# OpenTallas memory compiler (tools/mem_compiler), ASAP7 abstract view
VERSION 5.7 ;
BUSBITCHARS "[]" ;
DIVIDERCHAR "/" ;
PROPERTYDEFINITIONS
  MACRO width INTEGER ;
  MACRO depth INTEGER ;
  MACRO banks INTEGER ;
END PROPERTYDEFINITIONS
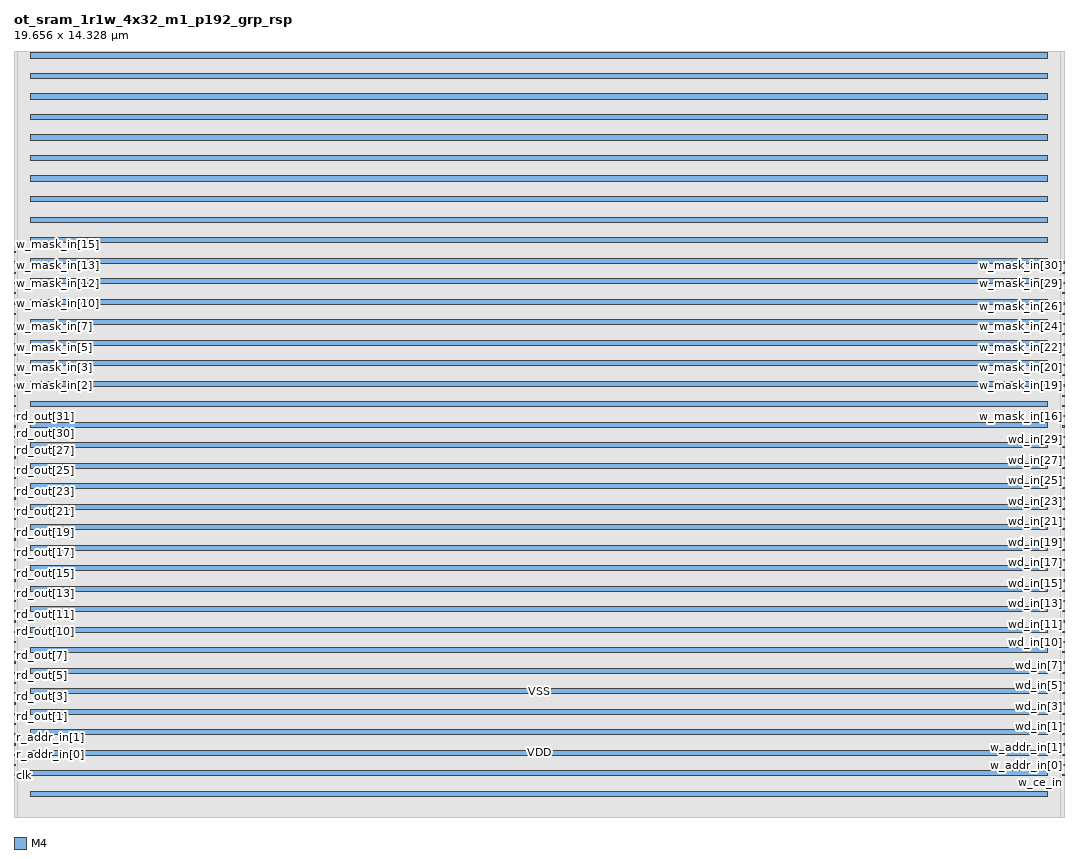
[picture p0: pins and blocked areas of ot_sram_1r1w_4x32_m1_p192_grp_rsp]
MACRO ot_sram_1r1w_4x32_m1_p192_grp_rsp
  PROPERTY width 32 ;
  PROPERTY depth 4 ;
  PROPERTY banks 1 ;
  FOREIGN ot_sram_1r1w_4x32_m1_p192_grp_rsp 0 0 ;
  SYMMETRY X Y R90 ;
  SIZE 19.656 BY 14.328 ;
  CLASS BLOCK ;
  PIN clk
    DIRECTION INPUT ;
    USE CLOCK ;
    SHAPE ABUTMENT ;
    PORT
      LAYER M4 ;
      RECT 0.000 0.768 0.024 0.792 ;
    END
  END clk
  PIN r_ce_in
    DIRECTION INPUT ;
    USE SIGNAL ;
    SHAPE ABUTMENT ;
    PORT
      LAYER M4 ;
      RECT 0.000 0.960 0.024 0.984 ;
    END
  END r_ce_in
  PIN r_addr_in[0]
    DIRECTION INPUT ;
    USE SIGNAL ;
    SHAPE ABUTMENT ;
    PORT
      LAYER M4 ;
      RECT 0.000 1.152 0.024 1.176 ;
    END
  END r_addr_in[0]
  PIN r_addr_in[1]
    DIRECTION INPUT ;
    USE SIGNAL ;
    SHAPE ABUTMENT ;
    PORT
      LAYER M4 ;
      RECT 0.000 1.344 0.024 1.368 ;
    END
  END r_addr_in[1]
  PIN rd_out[0]
    DIRECTION OUTPUT ;
    USE SIGNAL ;
    SHAPE ABUTMENT ;
    PORT
      LAYER M4 ;
      RECT 0.000 1.536 0.024 1.560 ;
    END
  END rd_out[0]
  PIN rd_out[1]
    DIRECTION OUTPUT ;
    USE SIGNAL ;
    SHAPE ABUTMENT ;
    PORT
      LAYER M4 ;
      RECT 0.000 1.728 0.024 1.752 ;
    END
  END rd_out[1]
  PIN rd_out[2]
    DIRECTION OUTPUT ;
    USE SIGNAL ;
    SHAPE ABUTMENT ;
    PORT
      LAYER M4 ;
      RECT 0.000 1.920 0.024 1.944 ;
    END
  END rd_out[2]
  PIN rd_out[3]
    DIRECTION OUTPUT ;
    USE SIGNAL ;
    SHAPE ABUTMENT ;
    PORT
      LAYER M4 ;
      RECT 0.000 2.112 0.024 2.136 ;
    END
  END rd_out[3]
  PIN rd_out[4]
    DIRECTION OUTPUT ;
    USE SIGNAL ;
    SHAPE ABUTMENT ;
    PORT
      LAYER M4 ;
      RECT 0.000 2.304 0.024 2.328 ;
    END
  END rd_out[4]
  PIN rd_out[5]
    DIRECTION OUTPUT ;
    USE SIGNAL ;
    SHAPE ABUTMENT ;
    PORT
      LAYER M4 ;
      RECT 0.000 2.496 0.024 2.520 ;
    END
  END rd_out[5]
  PIN rd_out[6]
    DIRECTION OUTPUT ;
    USE SIGNAL ;
    SHAPE ABUTMENT ;
    PORT
      LAYER M4 ;
      RECT 0.000 2.688 0.024 2.712 ;
    END
  END rd_out[6]
  PIN rd_out[7]
    DIRECTION OUTPUT ;
    USE SIGNAL ;
    SHAPE ABUTMENT ;
    PORT
      LAYER M4 ;
      RECT 0.000 2.880 0.024 2.904 ;
    END
  END rd_out[7]
  PIN rd_out[8]
    DIRECTION OUTPUT ;
    USE SIGNAL ;
    SHAPE ABUTMENT ;
    PORT
      LAYER M4 ;
      RECT 0.000 3.072 0.024 3.096 ;
    END
  END rd_out[8]
  PIN rd_out[9]
    DIRECTION OUTPUT ;
    USE SIGNAL ;
    SHAPE ABUTMENT ;
    PORT
      LAYER M4 ;
      RECT 0.000 3.264 0.024 3.288 ;
    END
  END rd_out[9]
  PIN rd_out[10]
    DIRECTION OUTPUT ;
    USE SIGNAL ;
    SHAPE ABUTMENT ;
    PORT
      LAYER M4 ;
      RECT 0.000 3.456 0.024 3.480 ;
    END
  END rd_out[10]
  PIN rd_out[11]
    DIRECTION OUTPUT ;
    USE SIGNAL ;
    SHAPE ABUTMENT ;
    PORT
      LAYER M4 ;
      RECT 0.000 3.648 0.024 3.672 ;
    END
  END rd_out[11]
  PIN rd_out[12]
    DIRECTION OUTPUT ;
    USE SIGNAL ;
    SHAPE ABUTMENT ;
    PORT
      LAYER M4 ;
      RECT 0.000 3.840 0.024 3.864 ;
    END
  END rd_out[12]
  PIN rd_out[13]
    DIRECTION OUTPUT ;
    USE SIGNAL ;
    SHAPE ABUTMENT ;
    PORT
      LAYER M4 ;
      RECT 0.000 4.032 0.024 4.056 ;
    END
  END rd_out[13]
  PIN rd_out[14]
    DIRECTION OUTPUT ;
    USE SIGNAL ;
    SHAPE ABUTMENT ;
    PORT
      LAYER M4 ;
      RECT 0.000 4.224 0.024 4.248 ;
    END
  END rd_out[14]
  PIN rd_out[15]
    DIRECTION OUTPUT ;
    USE SIGNAL ;
    SHAPE ABUTMENT ;
    PORT
      LAYER M4 ;
      RECT 0.000 4.416 0.024 4.440 ;
    END
  END rd_out[15]
  PIN rd_out[16]
    DIRECTION OUTPUT ;
    USE SIGNAL ;
    SHAPE ABUTMENT ;
    PORT
      LAYER M4 ;
      RECT 0.000 4.608 0.024 4.632 ;
    END
  END rd_out[16]
  PIN rd_out[17]
    DIRECTION OUTPUT ;
    USE SIGNAL ;
    SHAPE ABUTMENT ;
    PORT
      LAYER M4 ;
      RECT 0.000 4.800 0.024 4.824 ;
    END
  END rd_out[17]
  PIN rd_out[18]
    DIRECTION OUTPUT ;
    USE SIGNAL ;
    SHAPE ABUTMENT ;
    PORT
      LAYER M4 ;
      RECT 0.000 4.992 0.024 5.016 ;
    END
  END rd_out[18]
  PIN rd_out[19]
    DIRECTION OUTPUT ;
    USE SIGNAL ;
    SHAPE ABUTMENT ;
    PORT
      LAYER M4 ;
      RECT 0.000 5.184 0.024 5.208 ;
    END
  END rd_out[19]
  PIN rd_out[20]
    DIRECTION OUTPUT ;
    USE SIGNAL ;
    SHAPE ABUTMENT ;
    PORT
      LAYER M4 ;
      RECT 0.000 5.376 0.024 5.400 ;
    END
  END rd_out[20]
  PIN rd_out[21]
    DIRECTION OUTPUT ;
    USE SIGNAL ;
    SHAPE ABUTMENT ;
    PORT
      LAYER M4 ;
      RECT 0.000 5.568 0.024 5.592 ;
    END
  END rd_out[21]
  PIN rd_out[22]
    DIRECTION OUTPUT ;
    USE SIGNAL ;
    SHAPE ABUTMENT ;
    PORT
      LAYER M4 ;
      RECT 0.000 5.760 0.024 5.784 ;
    END
  END rd_out[22]
  PIN rd_out[23]
    DIRECTION OUTPUT ;
    USE SIGNAL ;
    SHAPE ABUTMENT ;
    PORT
      LAYER M4 ;
      RECT 0.000 5.952 0.024 5.976 ;
    END
  END rd_out[23]
  PIN rd_out[24]
    DIRECTION OUTPUT ;
    USE SIGNAL ;
    SHAPE ABUTMENT ;
    PORT
      LAYER M4 ;
      RECT 0.000 6.144 0.024 6.168 ;
    END
  END rd_out[24]
  PIN rd_out[25]
    DIRECTION OUTPUT ;
    USE SIGNAL ;
    SHAPE ABUTMENT ;
    PORT
      LAYER M4 ;
      RECT 0.000 6.336 0.024 6.360 ;
    END
  END rd_out[25]
  PIN rd_out[26]
    DIRECTION OUTPUT ;
    USE SIGNAL ;
    SHAPE ABUTMENT ;
    PORT
      LAYER M4 ;
      RECT 0.000 6.528 0.024 6.552 ;
    END
  END rd_out[26]
  PIN rd_out[27]
    DIRECTION OUTPUT ;
    USE SIGNAL ;
    SHAPE ABUTMENT ;
    PORT
      LAYER M4 ;
      RECT 0.000 6.720 0.024 6.744 ;
    END
  END rd_out[27]
  PIN rd_out[28]
    DIRECTION OUTPUT ;
    USE SIGNAL ;
    SHAPE ABUTMENT ;
    PORT
      LAYER M4 ;
      RECT 0.000 6.912 0.024 6.936 ;
    END
  END rd_out[28]
  PIN rd_out[29]
    DIRECTION OUTPUT ;
    USE SIGNAL ;
    SHAPE ABUTMENT ;
    PORT
      LAYER M4 ;
      RECT 0.000 7.104 0.024 7.128 ;
    END
  END rd_out[29]
  PIN rd_out[30]
    DIRECTION OUTPUT ;
    USE SIGNAL ;
    SHAPE ABUTMENT ;
    PORT
      LAYER M4 ;
      RECT 0.000 7.296 0.024 7.320 ;
    END
  END rd_out[30]
  PIN rd_out[31]
    DIRECTION OUTPUT ;
    USE SIGNAL ;
    SHAPE ABUTMENT ;
    PORT
      LAYER M4 ;
      RECT 0.000 7.488 0.024 7.512 ;
    END
  END rd_out[31]
  PIN w_mask_in[0]
    DIRECTION INPUT ;
    USE SIGNAL ;
    SHAPE ABUTMENT ;
    PORT
      LAYER M4 ;
      RECT 0.000 7.680 0.024 7.704 ;
    END
  END w_mask_in[0]
  PIN w_mask_in[1]
    DIRECTION INPUT ;
    USE SIGNAL ;
    SHAPE ABUTMENT ;
    PORT
      LAYER M4 ;
      RECT 0.000 7.872 0.024 7.896 ;
    END
  END w_mask_in[1]
  PIN w_mask_in[2]
    DIRECTION INPUT ;
    USE SIGNAL ;
    SHAPE ABUTMENT ;
    PORT
      LAYER M4 ;
      RECT 0.000 8.064 0.024 8.088 ;
    END
  END w_mask_in[2]
  PIN w_mask_in[3]
    DIRECTION INPUT ;
    USE SIGNAL ;
    SHAPE ABUTMENT ;
    PORT
      LAYER M4 ;
      RECT 0.000 8.256 0.024 8.280 ;
    END
  END w_mask_in[3]
  PIN w_mask_in[4]
    DIRECTION INPUT ;
    USE SIGNAL ;
    SHAPE ABUTMENT ;
    PORT
      LAYER M4 ;
      RECT 0.000 8.448 0.024 8.472 ;
    END
  END w_mask_in[4]
  PIN w_mask_in[5]
    DIRECTION INPUT ;
    USE SIGNAL ;
    SHAPE ABUTMENT ;
    PORT
      LAYER M4 ;
      RECT 0.000 8.640 0.024 8.664 ;
    END
  END w_mask_in[5]
  PIN w_mask_in[6]
    DIRECTION INPUT ;
    USE SIGNAL ;
    SHAPE ABUTMENT ;
    PORT
      LAYER M4 ;
      RECT 0.000 8.832 0.024 8.856 ;
    END
  END w_mask_in[6]
  PIN w_mask_in[7]
    DIRECTION INPUT ;
    USE SIGNAL ;
    SHAPE ABUTMENT ;
    PORT
      LAYER M4 ;
      RECT 0.000 9.024 0.024 9.048 ;
    END
  END w_mask_in[7]
  PIN w_mask_in[8]
    DIRECTION INPUT ;
    USE SIGNAL ;
    SHAPE ABUTMENT ;
    PORT
      LAYER M4 ;
      RECT 0.000 9.216 0.024 9.240 ;
    END
  END w_mask_in[8]
  PIN w_mask_in[9]
    DIRECTION INPUT ;
    USE SIGNAL ;
    SHAPE ABUTMENT ;
    PORT
      LAYER M4 ;
      RECT 0.000 9.408 0.024 9.432 ;
    END
  END w_mask_in[9]
  PIN w_mask_in[10]
    DIRECTION INPUT ;
    USE SIGNAL ;
    SHAPE ABUTMENT ;
    PORT
      LAYER M4 ;
      RECT 0.000 9.600 0.024 9.624 ;
    END
  END w_mask_in[10]
  PIN w_mask_in[11]
    DIRECTION INPUT ;
    USE SIGNAL ;
    SHAPE ABUTMENT ;
    PORT
      LAYER M4 ;
      RECT 0.000 9.792 0.024 9.816 ;
    END
  END w_mask_in[11]
  PIN w_mask_in[12]
    DIRECTION INPUT ;
    USE SIGNAL ;
    SHAPE ABUTMENT ;
    PORT
      LAYER M4 ;
      RECT 0.000 9.984 0.024 10.008 ;
    END
  END w_mask_in[12]
  PIN w_mask_in[13]
    DIRECTION INPUT ;
    USE SIGNAL ;
    SHAPE ABUTMENT ;
    PORT
      LAYER M4 ;
      RECT 0.000 10.176 0.024 10.200 ;
    END
  END w_mask_in[13]
  PIN w_mask_in[14]
    DIRECTION INPUT ;
    USE SIGNAL ;
    SHAPE ABUTMENT ;
    PORT
      LAYER M4 ;
      RECT 0.000 10.368 0.024 10.392 ;
    END
  END w_mask_in[14]
  PIN w_mask_in[15]
    DIRECTION INPUT ;
    USE SIGNAL ;
    SHAPE ABUTMENT ;
    PORT
      LAYER M4 ;
      RECT 0.000 10.560 0.024 10.584 ;
    END
  END w_mask_in[15]
  PIN w_ce_in
    DIRECTION INPUT ;
    USE SIGNAL ;
    SHAPE ABUTMENT ;
    PORT
      LAYER M4 ;
      RECT 19.632 0.768 19.656 0.792 ;
    END
  END w_ce_in
  PIN w_addr_in[0]
    DIRECTION INPUT ;
    USE SIGNAL ;
    SHAPE ABUTMENT ;
    PORT
      LAYER M4 ;
      RECT 19.632 0.960 19.656 0.984 ;
    END
  END w_addr_in[0]
  PIN w_addr_in[1]
    DIRECTION INPUT ;
    USE SIGNAL ;
    SHAPE ABUTMENT ;
    PORT
      LAYER M4 ;
      RECT 19.632 1.152 19.656 1.176 ;
    END
  END w_addr_in[1]
  PIN wd_in[0]
    DIRECTION INPUT ;
    USE SIGNAL ;
    SHAPE ABUTMENT ;
    PORT
      LAYER M4 ;
      RECT 19.632 1.344 19.656 1.368 ;
    END
  END wd_in[0]
  PIN wd_in[1]
    DIRECTION INPUT ;
    USE SIGNAL ;
    SHAPE ABUTMENT ;
    PORT
      LAYER M4 ;
      RECT 19.632 1.536 19.656 1.560 ;
    END
  END wd_in[1]
  PIN wd_in[2]
    DIRECTION INPUT ;
    USE SIGNAL ;
    SHAPE ABUTMENT ;
    PORT
      LAYER M4 ;
      RECT 19.632 1.728 19.656 1.752 ;
    END
  END wd_in[2]
  PIN wd_in[3]
    DIRECTION INPUT ;
    USE SIGNAL ;
    SHAPE ABUTMENT ;
    PORT
      LAYER M4 ;
      RECT 19.632 1.920 19.656 1.944 ;
    END
  END wd_in[3]
  PIN wd_in[4]
    DIRECTION INPUT ;
    USE SIGNAL ;
    SHAPE ABUTMENT ;
    PORT
      LAYER M4 ;
      RECT 19.632 2.112 19.656 2.136 ;
    END
  END wd_in[4]
  PIN wd_in[5]
    DIRECTION INPUT ;
    USE SIGNAL ;
    SHAPE ABUTMENT ;
    PORT
      LAYER M4 ;
      RECT 19.632 2.304 19.656 2.328 ;
    END
  END wd_in[5]
  PIN wd_in[6]
    DIRECTION INPUT ;
    USE SIGNAL ;
    SHAPE ABUTMENT ;
    PORT
      LAYER M4 ;
      RECT 19.632 2.496 19.656 2.520 ;
    END
  END wd_in[6]
  PIN wd_in[7]
    DIRECTION INPUT ;
    USE SIGNAL ;
    SHAPE ABUTMENT ;
    PORT
      LAYER M4 ;
      RECT 19.632 2.688 19.656 2.712 ;
    END
  END wd_in[7]
  PIN wd_in[8]
    DIRECTION INPUT ;
    USE SIGNAL ;
    SHAPE ABUTMENT ;
    PORT
      LAYER M4 ;
      RECT 19.632 2.880 19.656 2.904 ;
    END
  END wd_in[8]
  PIN wd_in[9]
    DIRECTION INPUT ;
    USE SIGNAL ;
    SHAPE ABUTMENT ;
    PORT
      LAYER M4 ;
      RECT 19.632 3.072 19.656 3.096 ;
    END
  END wd_in[9]
  PIN wd_in[10]
    DIRECTION INPUT ;
    USE SIGNAL ;
    SHAPE ABUTMENT ;
    PORT
      LAYER M4 ;
      RECT 19.632 3.264 19.656 3.288 ;
    END
  END wd_in[10]
  PIN wd_in[11]
    DIRECTION INPUT ;
    USE SIGNAL ;
    SHAPE ABUTMENT ;
    PORT
      LAYER M4 ;
      RECT 19.632 3.456 19.656 3.480 ;
    END
  END wd_in[11]
  PIN wd_in[12]
    DIRECTION INPUT ;
    USE SIGNAL ;
    SHAPE ABUTMENT ;
    PORT
      LAYER M4 ;
      RECT 19.632 3.648 19.656 3.672 ;
    END
  END wd_in[12]
  PIN wd_in[13]
    DIRECTION INPUT ;
    USE SIGNAL ;
    SHAPE ABUTMENT ;
    PORT
      LAYER M4 ;
      RECT 19.632 3.840 19.656 3.864 ;
    END
  END wd_in[13]
  PIN wd_in[14]
    DIRECTION INPUT ;
    USE SIGNAL ;
    SHAPE ABUTMENT ;
    PORT
      LAYER M4 ;
      RECT 19.632 4.032 19.656 4.056 ;
    END
  END wd_in[14]
  PIN wd_in[15]
    DIRECTION INPUT ;
    USE SIGNAL ;
    SHAPE ABUTMENT ;
    PORT
      LAYER M4 ;
      RECT 19.632 4.224 19.656 4.248 ;
    END
  END wd_in[15]
  PIN wd_in[16]
    DIRECTION INPUT ;
    USE SIGNAL ;
    SHAPE ABUTMENT ;
    PORT
      LAYER M4 ;
      RECT 19.632 4.416 19.656 4.440 ;
    END
  END wd_in[16]
  PIN wd_in[17]
    DIRECTION INPUT ;
    USE SIGNAL ;
    SHAPE ABUTMENT ;
    PORT
      LAYER M4 ;
      RECT 19.632 4.608 19.656 4.632 ;
    END
  END wd_in[17]
  PIN wd_in[18]
    DIRECTION INPUT ;
    USE SIGNAL ;
    SHAPE ABUTMENT ;
    PORT
      LAYER M4 ;
      RECT 19.632 4.800 19.656 4.824 ;
    END
  END wd_in[18]
  PIN wd_in[19]
    DIRECTION INPUT ;
    USE SIGNAL ;
    SHAPE ABUTMENT ;
    PORT
      LAYER M4 ;
      RECT 19.632 4.992 19.656 5.016 ;
    END
  END wd_in[19]
  PIN wd_in[20]
    DIRECTION INPUT ;
    USE SIGNAL ;
    SHAPE ABUTMENT ;
    PORT
      LAYER M4 ;
      RECT 19.632 5.184 19.656 5.208 ;
    END
  END wd_in[20]
  PIN wd_in[21]
    DIRECTION INPUT ;
    USE SIGNAL ;
    SHAPE ABUTMENT ;
    PORT
      LAYER M4 ;
      RECT 19.632 5.376 19.656 5.400 ;
    END
  END wd_in[21]
  PIN wd_in[22]
    DIRECTION INPUT ;
    USE SIGNAL ;
    SHAPE ABUTMENT ;
    PORT
      LAYER M4 ;
      RECT 19.632 5.568 19.656 5.592 ;
    END
  END wd_in[22]
  PIN wd_in[23]
    DIRECTION INPUT ;
    USE SIGNAL ;
    SHAPE ABUTMENT ;
    PORT
      LAYER M4 ;
      RECT 19.632 5.760 19.656 5.784 ;
    END
  END wd_in[23]
  PIN wd_in[24]
    DIRECTION INPUT ;
    USE SIGNAL ;
    SHAPE ABUTMENT ;
    PORT
      LAYER M4 ;
      RECT 19.632 5.952 19.656 5.976 ;
    END
  END wd_in[24]
  PIN wd_in[25]
    DIRECTION INPUT ;
    USE SIGNAL ;
    SHAPE ABUTMENT ;
    PORT
      LAYER M4 ;
      RECT 19.632 6.144 19.656 6.168 ;
    END
  END wd_in[25]
  PIN wd_in[26]
    DIRECTION INPUT ;
    USE SIGNAL ;
    SHAPE ABUTMENT ;
    PORT
      LAYER M4 ;
      RECT 19.632 6.336 19.656 6.360 ;
    END
  END wd_in[26]
  PIN wd_in[27]
    DIRECTION INPUT ;
    USE SIGNAL ;
    SHAPE ABUTMENT ;
    PORT
      LAYER M4 ;
      RECT 19.632 6.528 19.656 6.552 ;
    END
  END wd_in[27]
  PIN wd_in[28]
    DIRECTION INPUT ;
    USE SIGNAL ;
    SHAPE ABUTMENT ;
    PORT
      LAYER M4 ;
      RECT 19.632 6.720 19.656 6.744 ;
    END
  END wd_in[28]
  PIN wd_in[29]
    DIRECTION INPUT ;
    USE SIGNAL ;
    SHAPE ABUTMENT ;
    PORT
      LAYER M4 ;
      RECT 19.632 6.912 19.656 6.936 ;
    END
  END wd_in[29]
  PIN wd_in[30]
    DIRECTION INPUT ;
    USE SIGNAL ;
    SHAPE ABUTMENT ;
    PORT
      LAYER M4 ;
      RECT 19.632 7.104 19.656 7.128 ;
    END
  END wd_in[30]
  PIN wd_in[31]
    DIRECTION INPUT ;
    USE SIGNAL ;
    SHAPE ABUTMENT ;
    PORT
      LAYER M4 ;
      RECT 19.632 7.296 19.656 7.320 ;
    END
  END wd_in[31]
  PIN w_mask_in[16]
    DIRECTION INPUT ;
    USE SIGNAL ;
    SHAPE ABUTMENT ;
    PORT
      LAYER M4 ;
      RECT 19.632 7.488 19.656 7.512 ;
    END
  END w_mask_in[16]
  PIN w_mask_in[17]
    DIRECTION INPUT ;
    USE SIGNAL ;
    SHAPE ABUTMENT ;
    PORT
      LAYER M4 ;
      RECT 19.632 7.680 19.656 7.704 ;
    END
  END w_mask_in[17]
  PIN w_mask_in[18]
    DIRECTION INPUT ;
    USE SIGNAL ;
    SHAPE ABUTMENT ;
    PORT
      LAYER M4 ;
      RECT 19.632 7.872 19.656 7.896 ;
    END
  END w_mask_in[18]
  PIN w_mask_in[19]
    DIRECTION INPUT ;
    USE SIGNAL ;
    SHAPE ABUTMENT ;
    PORT
      LAYER M4 ;
      RECT 19.632 8.064 19.656 8.088 ;
    END
  END w_mask_in[19]
  PIN w_mask_in[20]
    DIRECTION INPUT ;
    USE SIGNAL ;
    SHAPE ABUTMENT ;
    PORT
      LAYER M4 ;
      RECT 19.632 8.256 19.656 8.280 ;
    END
  END w_mask_in[20]
  PIN w_mask_in[21]
    DIRECTION INPUT ;
    USE SIGNAL ;
    SHAPE ABUTMENT ;
    PORT
      LAYER M4 ;
      RECT 19.632 8.448 19.656 8.472 ;
    END
  END w_mask_in[21]
  PIN w_mask_in[22]
    DIRECTION INPUT ;
    USE SIGNAL ;
    SHAPE ABUTMENT ;
    PORT
      LAYER M4 ;
      RECT 19.632 8.640 19.656 8.664 ;
    END
  END w_mask_in[22]
  PIN w_mask_in[23]
    DIRECTION INPUT ;
    USE SIGNAL ;
    SHAPE ABUTMENT ;
    PORT
      LAYER M4 ;
      RECT 19.632 8.832 19.656 8.856 ;
    END
  END w_mask_in[23]
  PIN w_mask_in[24]
    DIRECTION INPUT ;
    USE SIGNAL ;
    SHAPE ABUTMENT ;
    PORT
      LAYER M4 ;
      RECT 19.632 9.024 19.656 9.048 ;
    END
  END w_mask_in[24]
  PIN w_mask_in[25]
    DIRECTION INPUT ;
    USE SIGNAL ;
    SHAPE ABUTMENT ;
    PORT
      LAYER M4 ;
      RECT 19.632 9.216 19.656 9.240 ;
    END
  END w_mask_in[25]
  PIN w_mask_in[26]
    DIRECTION INPUT ;
    USE SIGNAL ;
    SHAPE ABUTMENT ;
    PORT
      LAYER M4 ;
      RECT 19.632 9.408 19.656 9.432 ;
    END
  END w_mask_in[26]
  PIN w_mask_in[27]
    DIRECTION INPUT ;
    USE SIGNAL ;
    SHAPE ABUTMENT ;
    PORT
      LAYER M4 ;
      RECT 19.632 9.600 19.656 9.624 ;
    END
  END w_mask_in[27]
  PIN w_mask_in[28]
    DIRECTION INPUT ;
    USE SIGNAL ;
    SHAPE ABUTMENT ;
    PORT
      LAYER M4 ;
      RECT 19.632 9.792 19.656 9.816 ;
    END
  END w_mask_in[28]
  PIN w_mask_in[29]
    DIRECTION INPUT ;
    USE SIGNAL ;
    SHAPE ABUTMENT ;
    PORT
      LAYER M4 ;
      RECT 19.632 9.984 19.656 10.008 ;
    END
  END w_mask_in[29]
  PIN w_mask_in[30]
    DIRECTION INPUT ;
    USE SIGNAL ;
    SHAPE ABUTMENT ;
    PORT
      LAYER M4 ;
      RECT 19.632 10.176 19.656 10.200 ;
    END
  END w_mask_in[30]
  PIN w_mask_in[31]
    DIRECTION INPUT ;
    USE SIGNAL ;
    SHAPE ABUTMENT ;
    PORT
      LAYER M4 ;
      RECT 19.632 10.368 19.656 10.392 ;
    END
  END w_mask_in[31]
  PIN VDD
    DIRECTION INOUT ;
    USE POWER ;
    PORT
      LAYER M4 ;
      RECT 0.300 0.384 19.356 0.480 ;
      RECT 0.300 1.152 19.356 1.248 ;
      RECT 0.300 1.920 19.356 2.016 ;
      RECT 0.300 2.688 19.356 2.784 ;
      RECT 0.300 3.456 19.356 3.552 ;
      RECT 0.300 4.224 19.356 4.320 ;
      RECT 0.300 4.992 19.356 5.088 ;
      RECT 0.300 5.760 19.356 5.856 ;
      RECT 0.300 6.528 19.356 6.624 ;
      RECT 0.300 7.296 19.356 7.392 ;
      RECT 0.300 8.064 19.356 8.160 ;
      RECT 0.300 8.832 19.356 8.928 ;
      RECT 0.300 9.600 19.356 9.696 ;
      RECT 0.300 10.368 19.356 10.464 ;
      RECT 0.300 11.136 19.356 11.232 ;
      RECT 0.300 11.904 19.356 12.000 ;
      RECT 0.300 12.672 19.356 12.768 ;
      RECT 0.300 13.440 19.356 13.536 ;
      RECT 0.300 14.208 19.356 14.304 ;
    END
  END VDD
  PIN VSS
    DIRECTION INOUT ;
    USE GROUND ;
    PORT
      LAYER M4 ;
      RECT 0.300 0.768 19.356 0.864 ;
      RECT 0.300 1.536 19.356 1.632 ;
      RECT 0.300 2.304 19.356 2.400 ;
      RECT 0.300 3.072 19.356 3.168 ;
      RECT 0.300 3.840 19.356 3.936 ;
      RECT 0.300 4.608 19.356 4.704 ;
      RECT 0.300 5.376 19.356 5.472 ;
      RECT 0.300 6.144 19.356 6.240 ;
      RECT 0.300 6.912 19.356 7.008 ;
      RECT 0.300 7.680 19.356 7.776 ;
      RECT 0.300 8.448 19.356 8.544 ;
      RECT 0.300 9.216 19.356 9.312 ;
      RECT 0.300 9.984 19.356 10.080 ;
      RECT 0.300 10.752 19.356 10.848 ;
      RECT 0.300 11.520 19.356 11.616 ;
      RECT 0.300 12.288 19.356 12.384 ;
      RECT 0.300 13.056 19.356 13.152 ;
      RECT 0.300 13.824 19.356 13.920 ;
    END
  END VSS
  OBS
    LAYER M1 ;
    RECT 0 0 19.656 14.328 ;
    LAYER M2 ;
    RECT 0 0 19.656 14.328 ;
    LAYER M3 ;
    RECT 0 0 19.656 14.328 ;
    LAYER M4 ;
    RECT 0.072 0 19.584 14.328 ;
  END
END ot_sram_1r1w_4x32_m1_p192_grp_rsp

END LIBRARY
